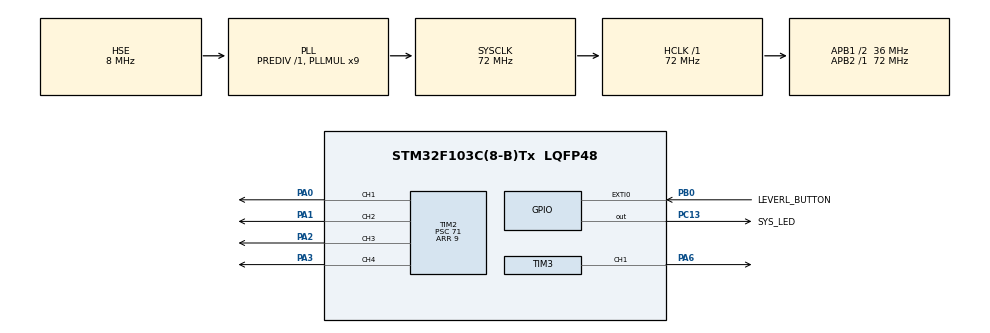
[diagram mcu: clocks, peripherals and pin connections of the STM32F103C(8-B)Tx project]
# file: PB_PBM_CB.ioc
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Mcu.Family=STM32F1
Mcu.Name=STM32F103C(8-B)Tx
Mcu.Package=LQFP48
NVIC.EXTI0_IRQn=true\:0\:0\:false\:false\:true\:true\:true\:true
NVIC.PriorityGroup=NVIC_PRIORITYGROUP_4
NVIC.TIM1_UP_IRQn=true\:0\:0\:false\:false\:true\:true\:true\:true
NVIC.TIM2_IRQn=true\:0\:0\:false\:false\:true\:true\:true\:true
PA0-WKUP.Signal=S_TIM2_CH1_ETR
PA1.Signal=S_TIM2_CH2
PA13.Mode=Serial_Wire
PA13.Signal=SYS_JTMS-SWDIO
PA14.Mode=Serial_Wire
PA14.Signal=SYS_JTCK-SWCLK
PA2.Signal=S_TIM2_CH3
PA3.Signal=S_TIM2_CH4
PA6.Signal=S_TIM3_CH1
PB0.GPIO_Label=LEVERL_BUTTON
PB0.GPIO_ModeDefaultEXTI=GPIO_MODE_IT_FALLING
PB0.GPIO_PuPd=GPIO_PULLUP
PB0.Signal=GPXTI0
PC13-TAMPER-RTC.GPIO_Label=SYS_LED
PC13-TAMPER-RTC.GPIO_ModeDefaultOutputPP=GPIO_MODE_OUTPUT_OD
PC13-TAMPER-RTC.GPIO_PuPd=GPIO_NOPULL
PC13-TAMPER-RTC.Signal=GPIO_Output
PD0-OSC_IN.Mode=HSE-External-Oscillator
PD0-OSC_IN.Signal=RCC_OSC_IN
PD1-OSC_OUT.Mode=HSE-External-Oscillator
PD1-OSC_OUT.Signal=RCC_OSC_OUT
ProjectManager.HeapSize=0x200
ProjectManager.StackSize=0x400
ProjectManager.TargetToolchain=STM32CubeIDE
RCC.AHBFreq_Value=72000000
RCC.APB1CLKDivider=RCC_HCLK_DIV2
RCC.APB1Freq_Value=36000000
RCC.APB1TimFreq_Value=72000000
RCC.APB2Freq_Value=72000000
RCC.APB2TimFreq_Value=72000000
RCC.HCLKFreq_Value=72000000
RCC.PLLMUL=RCC_PLL_MUL9
RCC.PLLSourceVirtual=RCC_PLLSOURCE_HSE
RCC.SYSCLKFreq_VALUE=72000000
RCC.SYSCLKSource=RCC_SYSCLKSOURCE_PLLCLK
RCC.USBFreq_Value=72000000
SH.S_TIM2_CH1_ETR.0=TIM2_CH1,PWM Generation1 CH1
SH.S_TIM2_CH2.0=TIM2_CH2,PWM Generation2 CH2
SH.S_TIM2_CH3.0=TIM2_CH3,PWM Generation3 CH3
SH.S_TIM2_CH4.0=TIM2_CH4,PWM Generation4 CH4
SH.S_TIM3_CH1.0=TIM3_CH1,PWM Generation1 CH1
TIM1.AutoReloadPreload=TIM_AUTORELOAD_PRELOAD_ENABLE
TIM1.Period=9999
TIM1.Prescaler=719
TIM2.AutoReloadPreload=TIM_AUTORELOAD_PRELOAD_ENABLE
TIM2.Channel-PWM\ Generation1\ CH1=TIM_CHANNEL_1
TIM2.Channel-PWM\ Generation2\ CH2=TIM_CHANNEL_2
TIM2.Channel-PWM\ Generation3\ CH3=TIM_CHANNEL_3
TIM2.Channel-PWM\ Generation4\ CH4=TIM_CHANNEL_4
TIM2.OCMode_PWM-PWM\ Generation1\ CH1=TIM_OCMODE_PWM1
TIM2.OCPolarity_1=TIM_OCPOLARITY_HIGH
TIM2.Period=9
TIM2.Prescaler=71
TIM2.Pulse-PWM\ Generation1\ CH1=10
TIM2.Pulse-PWM\ Generation2\ CH2=0
TIM2.Pulse-PWM\ Generation3\ CH3=0
TIM2.Pulse-PWM\ Generation4\ CH4=0
TIM3.AutoReloadPreload=TIM_AUTORELOAD_PRELOAD_ENABLE
TIM3.Channel-PWM\ Generation1\ CH1=TIM_CHANNEL_1
TIM3.Period=10
TIM3.Prescaler=71
VP_TIM1_VS_ClockSourceINT.Mode=Internal
VP_TIM1_VS_ClockSourceITR.Mode=TriggerSource_ITR0
VP_TIM2_VS_ClockSourceINT.Mode=Internal
VP_TIM3_VS_ClockSourceINT.Mode=Internal
board=custom

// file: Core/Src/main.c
/* USER CODE BEGIN Header */
/**
  ******************************************************************************
  * @file           : main.c
  * @brief          : Main program body
  * 0510
  ******************************************************************************
  * @attention
  *
  * Copyright (c) 2024 STMicroelectronics.
  * All rights reserved.
  *
  * This software is licensed under terms that can be found in the LICENSE file
  * in the root directory of this software component.
  * If no LICENSE file comes with this software, it is provided AS-IS.
  *
  ******************************************************************************
  */
/* USER CODE END Header */
#include "main.h"

TIM_HandleTypeDef htim1;
TIM_HandleTypeDef htim2;
TIM_HandleTypeDef htim3;

uint8_t buttonCheckFlag 		= 0;

uint32_t dutyButtonCounter 		= 0;
uint32_t currentButtonCounter 	= 0;
uint32_t pulseCounter 			= 0;
uint32_t ledCounter 			= 0;
uint32_t ledCurrFlashCounter	= 0;
uint32_t ledDutyFlashCounter	= 0;
uint32_t ledFlashCounter			= 0;

uint32_t pulseValueCurrent 		= CURRENT_INIT;
uint32_t pulseValueCurrentIdle 		= CURRENT_IDLE;

uint32_t pulseValueDuty	 	= DUTY_INIT;

void SystemClock_Config(void);
static void MX_GPIO_Init(void);
static void MX_TIM2_Init(void);
static void MX_TIM1_Init(void);
static void MX_TIM3_Init(void);

/* USER CODE BEGIN 0 */
void LEDUpdate(void)
{
	ledCounter++;
	if(ledCounter == 200)
	{
		ledFlashCounter++;
		if((ledFlashCounter)<= (pulseValueDuty/DUTY_ADD_STEP))
		{
			HAL_GPIO_WritePin(DUTY_LED_GPIO_Port, DUTY_LED_Pin, GPIO_PIN_RESET);
		}

		if((ledFlashCounter)<= (pulseValueCurrent/CURRENT_ADD_STEP))
		{
			HAL_GPIO_WritePin(CURR_LED_GPIO_Port, CURR_LED_Pin, GPIO_PIN_RESET);
		}
		HAL_GPIO_WritePin(SYS_LED_GPIO_Port, SYS_LED_Pin, GPIO_PIN_RESET);
	}
	else if(ledCounter == 400)
	{
		HAL_GPIO_WritePin(CURR_LED_GPIO_Port, CURR_LED_Pin, GPIO_PIN_SET);
		HAL_GPIO_WritePin(DUTY_LED_GPIO_Port, DUTY_LED_Pin, GPIO_PIN_SET);
		HAL_GPIO_WritePin(SYS_LED_GPIO_Port, SYS_LED_Pin, GPIO_PIN_SET);

		ledCounter = 0;
		ledFlashCounter %= 8;
	}

}

void CheckButtonAndImplement()
{
	if(!buttonCheckFlag)
		return;

	buttonCheckFlag = 0;

	/* Output duty current button check */
	if(HAL_GPIO_ReadPin(DUTY_BUTTON_GPIO_Port, DUTY_BUTTON_Pin))
	{
		if(dutyButtonCounter>0)
			dutyButtonCounter--;
	}
	else if(dutyButtonCounter < BUTTON_CONFIRM_TIME)
	{
		dutyButtonCounter++;
	}
	else if(dutyButtonCounter == BUTTON_CONFIRM_TIME)
	{
		dutyButtonCounter++;
		pulseValueDuty += DUTY_ADD_STEP;
		pulseValueDuty %= DUTY_ADD_STEP + DUTY_LIMIT;

		ledCounter = 0;
		ledFlashCounter = 0;
	}

	/* Output current button check */
	if(HAL_GPIO_ReadPin(CURRENT_BUTTON_GPIO_Port, CURRENT_BUTTON_Pin))
	{
		if(currentButtonCounter>0)
			currentButtonCounter--;
	}
	else if(currentButtonCounter < BUTTON_CONFIRM_TIME)
	{
		currentButtonCounter++;
	}
	else if(currentButtonCounter == BUTTON_CONFIRM_TIME)
	{
		currentButtonCounter++;
		pulseValueCurrent += CURRENT_ADD_STEP;
		pulseValueCurrent %= CURRENT_ADD_STEP + CURRENT_LIMIT;

		ledCounter = 0;
		ledFlashCounter = 0;
	}

	LEDUpdate();

	return;
}

/* USER CODE END 0 */

int main(void)
{

  /* MCU Configuration--------------------------------------------------------*/

  /* Reset of all peripherals, Initializes the Flash interface and the Systick. */
  HAL_Init();

  /* Configure the system clock */
  SystemClock_Config();

  /* Initialize all configured peripherals */
  MX_GPIO_Init();
  MX_TIM2_Init();
  MX_TIM1_Init();	// period 1ms
  MX_TIM3_Init();	// frequence 100kHz
  /* USER CODE BEGIN 2 */
  HAL_TIM_PWM_Start(&htim2, TIM_CHANNEL_1);
  HAL_TIM_PWM_Start(&htim2, TIM_CHANNEL_2);
  HAL_TIM_PWM_Start(&htim3, TIM_CHANNEL_1);
  /* USER CODE END 2 */

  /* Infinite loop */
  while (1)
  {
	  CheckButtonAndImplement();
  }
}

void SystemClock_Config(void)
{
  RCC_OscInitTypeDef RCC_OscInitStruct = {0};
  RCC_ClkInitTypeDef RCC_ClkInitStruct = {0};

  /** Initializes the RCC Oscillators according to the specified parameters
  * in the RCC_OscInitTypeDef structure.
  */
  RCC_OscInitStruct.OscillatorType = RCC_OSCILLATORTYPE_HSE;
  RCC_OscInitStruct.HSEState = RCC_HSE_ON;
  RCC_OscInitStruct.HSEPredivValue = RCC_HSE_PREDIV_DIV1;
  RCC_OscInitStruct.HSIState = RCC_HSI_ON;
  RCC_OscInitStruct.PLL.PLLState = RCC_PLL_ON;
  RCC_OscInitStruct.PLL.PLLSource = RCC_PLLSOURCE_HSE;
  RCC_OscInitStruct.PLL.PLLMUL = RCC_PLL_MUL9;
  if (HAL_RCC_OscConfig(&RCC_OscInitStruct) != HAL_OK)
  {
    Error_Handler();
  }

  /** Initializes the CPU, AHB and APB buses clocks
  */
  RCC_ClkInitStruct.ClockType = RCC_CLOCKTYPE_HCLK|RCC_CLOCKTYPE_SYSCLK
                              |RCC_CLOCKTYPE_PCLK1|RCC_CLOCKTYPE_PCLK2;
  RCC_ClkInitStruct.SYSCLKSource = RCC_SYSCLKSOURCE_PLLCLK;
  RCC_ClkInitStruct.AHBCLKDivider = RCC_SYSCLK_DIV1;
  RCC_ClkInitStruct.APB1CLKDivider = RCC_HCLK_DIV2;
  RCC_ClkInitStruct.APB2CLKDivider = RCC_HCLK_DIV1;

  if (HAL_RCC_ClockConfig(&RCC_ClkInitStruct, FLASH_LATENCY_2) != HAL_OK)
  {
    Error_Handler();
  }
}

static void MX_TIM1_Init(void)
{

  TIM_ClockConfigTypeDef sClockSourceConfig = {0};
  TIM_SlaveConfigTypeDef sSlaveConfig = {0};
  TIM_MasterConfigTypeDef sMasterConfig = {0};

  htim1.Instance = TIM1;
  htim1.Init.Prescaler = 71;
  htim1.Init.CounterMode = TIM_COUNTERMODE_UP;
  htim1.Init.Period = 999;
  htim1.Init.ClockDivision = TIM_CLOCKDIVISION_DIV1;
  htim1.Init.RepetitionCounter = 0;
  htim1.Init.AutoReloadPreload = TIM_AUTORELOAD_PRELOAD_ENABLE;
  if (HAL_TIM_Base_Init(&htim1) != HAL_OK)
  {
    Error_Handler();
  }
  sClockSourceConfig.ClockSource = TIM_CLOCKSOURCE_INTERNAL;
  if (HAL_TIM_ConfigClockSource(&htim1, &sClockSourceConfig) != HAL_OK)
  {
    Error_Handler();
  }
  sSlaveConfig.SlaveMode = TIM_SLAVEMODE_DISABLE;
  sSlaveConfig.InputTrigger = TIM_TS_ITR0;
  if (HAL_TIM_SlaveConfigSynchro(&htim1, &sSlaveConfig) != HAL_OK)
  {
    Error_Handler();
  }
  sMasterConfig.MasterOutputTrigger = TIM_TRGO_RESET;
  sMasterConfig.MasterSlaveMode = TIM_MASTERSLAVEMODE_DISABLE;
  if (HAL_TIMEx_MasterConfigSynchronization(&htim1, &sMasterConfig) != HAL_OK)
  {
    Error_Handler();
  }
  /* USER CODE BEGIN TIM1_Init 2 */
  HAL_TIM_Base_Start_IT(&htim1);
  /* USER CODE END TIM1_Init 2 */

}

static void MX_TIM2_Init(void)
{

  TIM_ClockConfigTypeDef sClockSourceConfig = {0};
  TIM_MasterConfigTypeDef sMasterConfig = {0};
  TIM_OC_InitTypeDef sConfigOC = {0};

  htim2.Instance = TIM2;
  htim2.Init.Prescaler = 719;
  htim2.Init.CounterMode = TIM_COUNTERMODE_UP;
  htim2.Init.Period = 2999;
  htim2.Init.ClockDivision = TIM_CLOCKDIVISION_DIV1;
  htim2.Init.AutoReloadPreload = TIM_AUTORELOAD_PRELOAD_ENABLE;
  if (HAL_TIM_Base_Init(&htim2) != HAL_OK)
  {
    Error_Handler();
  }
  sClockSourceConfig.ClockSource = TIM_CLOCKSOURCE_INTERNAL;
  if (HAL_TIM_ConfigClockSource(&htim2, &sClockSourceConfig) != HAL_OK)
  {
    Error_Handler();
  }
  if (HAL_TIM_PWM_Init(&htim2) != HAL_OK)
  {
    Error_Handler();
  }
  sMasterConfig.MasterOutputTrigger = TIM_TRGO_RESET;
  sMasterConfig.MasterSlaveMode = TIM_MASTERSLAVEMODE_DISABLE;
  if (HAL_TIMEx_MasterConfigSynchronization(&htim2, &sMasterConfig) != HAL_OK)
  {
    Error_Handler();
  }
  sConfigOC.OCMode = TIM_OCMODE_PWM1;
  sConfigOC.Pulse = 3000;
  sConfigOC.OCPolarity = TIM_OCPOLARITY_HIGH;
  sConfigOC.OCFastMode = TIM_OCFAST_DISABLE;
  if (HAL_TIM_PWM_ConfigChannel(&htim2, &sConfigOC, TIM_CHANNEL_1) != HAL_OK)
  {
    Error_Handler();
  }
  sConfigOC.Pulse = 3000;
  if (HAL_TIM_PWM_ConfigChannel(&htim2, &sConfigOC, TIM_CHANNEL_2) != HAL_OK)
  {
    Error_Handler();
  }

  HAL_TIM_MspPostInit(&htim2);

}

static void MX_TIM3_Init(void)
{

  TIM_ClockConfigTypeDef sClockSourceConfig = {0};
  TIM_MasterConfigTypeDef sMasterConfig = {0};
  TIM_OC_InitTypeDef sConfigOC = {0};

  htim3.Instance = TIM3;
  htim3.Init.Prescaler = 71;
  htim3.Init.CounterMode = TIM_COUNTERMODE_UP;
  htim3.Init.Period = CURRENT_PULSE_FULLLEVEL - 1;
  htim3.Init.ClockDivision = TIM_CLOCKDIVISION_DIV1;
  htim3.Init.AutoReloadPreload = TIM_AUTORELOAD_PRELOAD_ENABLE;
  if (HAL_TIM_Base_Init(&htim3) != HAL_OK)
  {
    Error_Handler();
  }
  sClockSourceConfig.ClockSource = TIM_CLOCKSOURCE_INTERNAL;
  if (HAL_TIM_ConfigClockSource(&htim3, &sClockSourceConfig) != HAL_OK)
  {
    Error_Handler();
  }
  if (HAL_TIM_PWM_Init(&htim3) != HAL_OK)
  {
    Error_Handler();
  }
  sMasterConfig.MasterOutputTrigger = TIM_TRGO_RESET;
  sMasterConfig.MasterSlaveMode = TIM_MASTERSLAVEMODE_DISABLE;
  if (HAL_TIMEx_MasterConfigSynchronization(&htim3, &sMasterConfig) != HAL_OK)
  {
    Error_Handler();
  }
  sConfigOC.OCMode = TIM_OCMODE_PWM1;
  sConfigOC.Pulse = pulseValueCurrentIdle;
  sConfigOC.OCPolarity = TIM_OCPOLARITY_HIGH;
  sConfigOC.OCFastMode = TIM_OCFAST_DISABLE;
  if (HAL_TIM_PWM_ConfigChannel(&htim3, &sConfigOC, TIM_CHANNEL_1) != HAL_OK)
  {
    Error_Handler();
  }
  HAL_TIM_MspPostInit(&htim3);

}

static void MX_GPIO_Init(void)
{
  GPIO_InitTypeDef GPIO_InitStruct = {0};

  /* GPIO Ports Clock Enable */
  __HAL_RCC_GPIOC_CLK_ENABLE();
  __HAL_RCC_GPIOD_CLK_ENABLE();
  __HAL_RCC_GPIOA_CLK_ENABLE();
  __HAL_RCC_GPIOB_CLK_ENABLE();

  /*Configure GPIO pin Output Level */
  HAL_GPIO_WritePin(CURR_LED_GPIO_Port, CURR_LED_Pin, GPIO_PIN_SET);
  HAL_GPIO_WritePin(DUTY_LED_GPIO_Port, DUTY_LED_Pin, GPIO_PIN_SET);
  HAL_GPIO_WritePin(SYS_LED_GPIO_Port, SYS_LED_Pin, GPIO_PIN_SET);

  /*Configure GPIO pin : LED_Pin */
  GPIO_InitStruct.Pin = CURR_LED_Pin | DUTY_LED_Pin | SYS_LED_Pin;
  GPIO_InitStruct.Mode = GPIO_MODE_OUTPUT_OD;
  GPIO_InitStruct.Pull = GPIO_NOPULL;
  GPIO_InitStruct.Speed = GPIO_SPEED_FREQ_LOW;
  HAL_GPIO_Init(CURR_LED_GPIO_Port, &GPIO_InitStruct);

  /*Configure GPIO pin : BUTTON_Pin */
  GPIO_InitStruct.Pin = FREQ_BUTTON_Pin;
  GPIO_InitStruct.Mode = GPIO_MODE_INPUT;
  GPIO_InitStruct.Pull = GPIO_PULLUP;
  HAL_GPIO_Init(FREQ_BUTTON_GPIO_Port, &GPIO_InitStruct);

  GPIO_InitStruct.Pin = DUTY_BUTTON_Pin;
  GPIO_InitStruct.Mode = GPIO_MODE_INPUT;
  GPIO_InitStruct.Pull = GPIO_PULLUP;
  HAL_GPIO_Init(DUTY_BUTTON_GPIO_Port, &GPIO_InitStruct);

  GPIO_InitStruct.Pin = CURRENT_BUTTON_Pin;
  GPIO_InitStruct.Mode = GPIO_MODE_IT_FALLING;
  GPIO_InitStruct.Pull = GPIO_PULLUP;
  HAL_GPIO_Init(CURRENT_BUTTON_GPIO_Port, &GPIO_InitStruct);

}

void Error_Handler(void)
{
  /* USER CODE BEGIN Error_Handler_Debug */
  /* User can add his own implementation to report the HAL error return state */
  __disable_irq();
  while (1)
  {
	  HAL_GPIO_WritePin(GPIOC, GPIO_PIN_13, GPIO_PIN_SET);

  }
  /* USER CODE END Error_Handler_Debug */
}
